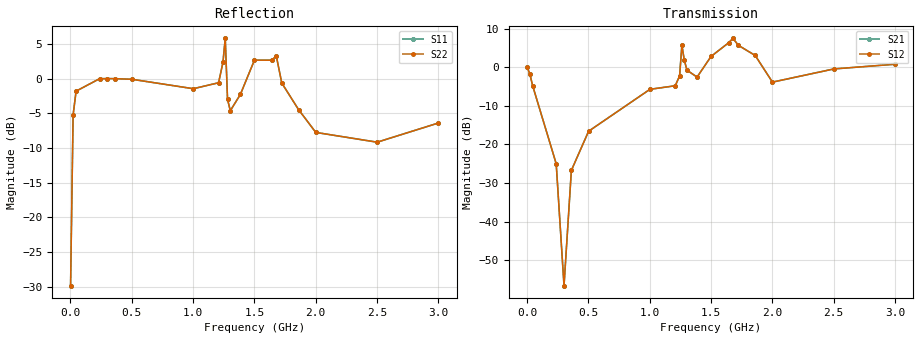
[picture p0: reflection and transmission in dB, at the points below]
!s-Parameter Generated by FASTRON Sdn. Bhd.
!FASTRON P/N : MICC-R56X
!Keysight Technologies,E4991B,MY54100416,A.01.15
!Date: Fri Aug 21 13:02:05 2026
!Version  : Rev00 Fri Aug 21 13:02:05 2026
!Data & Calibration Information:
!PortZ  Port1:50+j0  Port2:50+j0
!When reading, reference impedance value at option line is always used.
! Remarks : This data is being provided solely for informational purposes.
!Freq	S11	S21	S12	S22
# Hz S dB R 50
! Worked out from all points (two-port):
!   1601 points, 1 MHz to 3 GHz, reference 50 ohm
!   highest |S21| = 7.52 dB at 1.679 GHz (marker M1); lowest = -56.6 dB at 300.9 MHz (marker M2)
!   |S21| within 3 dB of the highest: 1.259 GHz to 1.271 GHz (12.55 MHz wide, 0.992 % of centre); 1.533 GHz to 1.756 GHz (223 MHz wide, 13.6 % of centre)
!   lowest |S11| = -29.9 dB at 1 MHz (marker M3), VSWR 1.07, Z = 50.3 + j3.21 ohm
!   |S11| at or under -10 dB: start of sweep to 10.99 MHz
!   |S22| runs from -29.9 to 5.9 dB; largest |S21 - S12| = 0
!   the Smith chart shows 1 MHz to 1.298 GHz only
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1000000  -29.87 83.2  -0.03 -1.8  -0.03 -1.8  -29.87 83.2
2.161812e7  -5.26 55.7  -1.66 -33.1  -1.66 -33.1  -5.26 55.7
4.5985e7  -1.82 34.9  -4.86 -54.2  -4.86 -54.2  -1.82 34.9
2.371712e8  -0.03 3.2  -24.98 -85.1  -24.98 -85.1  -0.03 3.2
3.009e8  -0.01 0.0  -56.61 -4.4  -56.61 -4.4  -0.01 0.0
3.6088e8  -0.02 -2.6  -26.71 85.4  -26.71 85.4  -0.02 -2.6
5.014581e8  -0.11 -8.5  -16.56 80.7  -16.56 80.7  -0.11 -8.5
1.001916e9  -1.47 -31.3  -5.69 57.6  -5.69 57.6  -1.47 -31.3
1.208098e9  -0.61 -34.5  -4.77 66.3  -4.77 66.3  -0.61 -34.5
1.243711e9  2.32 -36.3  -2.22 93.9  -2.22 93.9  2.32 -36.3
1.262454e9  5.79 -75.0  5.78 75.2  5.78 75.2  5.79 -75.0
1.281198e9  -3.00 -92.8  1.96 34.4  1.96 34.4  -3.00 -92.8
1.303691e9  -4.65 -64.7  -0.74 35.2  -0.74 35.2  -4.65 -64.7
1.386163e9  -2.28 -47.9  -2.52 49.7  -2.52 49.7  -2.28 -47.9
1.5005e9  2.65 -70.3  2.85 67.0  2.85 67.0  2.65 -70.3
1.642952e9  2.64 -123.4  6.36 32.9  6.36 32.9  2.64 -123.4
1.678566e9  3.28 -149.8  7.52 18.0  7.52 18.0  3.28 -149.8
1.723551e9  -0.65 178.0  5.70 -0.9  5.70 -0.9  -0.65 178.0
1.86038e9  -4.48 124.4  3.08 -20.2  3.08 -20.2  -4.48 124.4
2.000958e9  -7.77 22.9  -3.83 -14.3  -3.83 -14.3  -7.77 22.9
2.501416e9  -9.18 -72.3  -0.41 20.3  -0.41 20.3  -9.18 -72.3
3e9  -6.42 -88.7  0.81 25.8  0.81 25.8  -6.42 -88.7
